One B-rep face of a CAD part: STEP entity #880.
In plain terms, the planar face has unit normal (1, 0, 0).
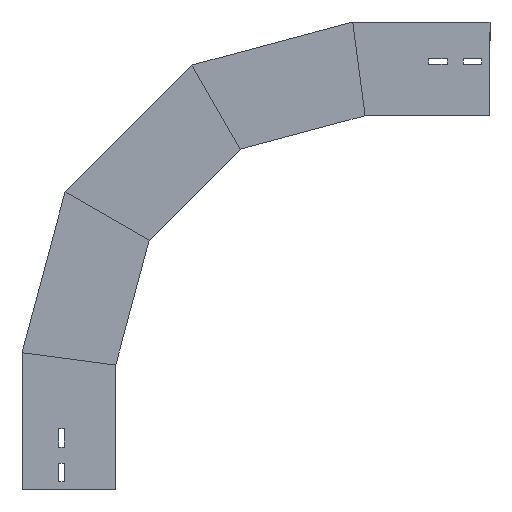
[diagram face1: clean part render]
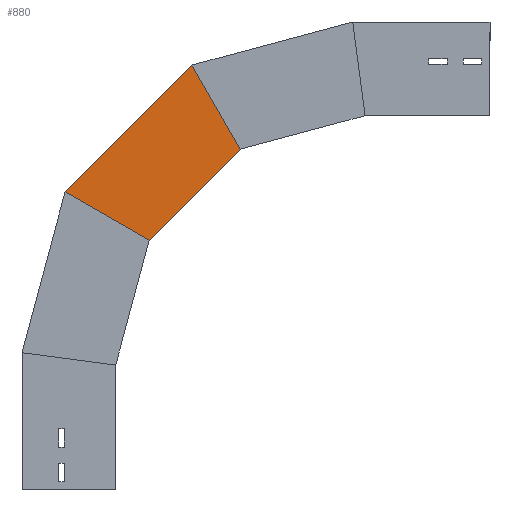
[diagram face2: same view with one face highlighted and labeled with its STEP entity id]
Its self-contained STEP definition (entity closure, numbers rounded to 3 decimals):
#38 = VECTOR ( 'NONE', #432, 1000. ) ;
#131 = LINE ( 'NONE', #1875, #38 ) ;
#132 = AXIS2_PLACEMENT_3D ( 'NONE', #1289, #1869, #224 ) ;
#134 = ORIENTED_EDGE ( 'NONE', *, *, #1280, .F. ) ;
#196 = EDGE_CURVE ( 'NONE', #447, #277, #1437, .T. ) ;
#224 = DIRECTION ( 'NONE',  ( 0., 0., -1. ) ) ;
#277 = VERTEX_POINT ( 'NONE', #496 ) ;
#383 = FACE_OUTER_BOUND ( 'NONE', #837, .T. ) ;
#409 = ORIENTED_EDGE ( 'NONE', *, *, #702, .T. ) ;
#413 = DIRECTION ( 'NONE',  ( 0., -0.707, 0.707 ) ) ;
#429 = CARTESIAN_POINT ( 'NONE',  ( 0., -40.117, 299.719 ) ) ;
#432 = DIRECTION ( 'NONE',  ( 0., -0.5, -0.866 ) ) ;
#447 = VERTEX_POINT ( 'NONE', #429 ) ;
#496 = CARTESIAN_POINT ( 'NONE',  ( 0., -149.719, 409.32 ) ) ;
#534 = DIRECTION ( 'NONE',  ( 0., -0.866, -0.5 ) ) ;
#545 = LINE ( 'NONE', #1715, #1818 ) ;
#583 = VERTEX_POINT ( 'NONE', #1326 ) ;
#628 = CARTESIAN_POINT ( 'NONE',  ( 0., -91.484, 510.185 ) ) ;
#702 = EDGE_CURVE ( 'NONE', #583, #1456, #1086, .T. ) ;
#734 = CARTESIAN_POINT ( 'NONE',  ( 0., -16.599, 276.201 ) ) ;
#788 = DIRECTION ( 'NONE',  ( 0., -0.707, 0.707 ) ) ;
#808 = VECTOR ( 'NONE', #413, 1000. ) ;
#837 = EDGE_LOOP ( 'NONE', ( #409, #1589, #1087, #134 ) ) ;
#880 = ADVANCED_FACE ( 'NONE', ( #383 ), #1555, .T. ) ;
#1086 = LINE ( 'NONE', #1504, #1170 ) ;
#1087 = ORIENTED_EDGE ( 'NONE', *, *, #196, .F. ) ;
#1170 = VECTOR ( 'NONE', #788, 1000. ) ;
#1280 = EDGE_CURVE ( 'NONE', #583, #447, #545, .T. ) ;
#1289 = CARTESIAN_POINT ( 'NONE',  ( 0., -16.599, 276.201 ) ) ;
#1326 = CARTESIAN_POINT ( 'NONE',  ( 0., 60.748, 357.953 ) ) ;
#1437 = LINE ( 'NONE', #734, #808 ) ;
#1456 = VERTEX_POINT ( 'NONE', #628 ) ;
#1504 = CARTESIAN_POINT ( 'NONE',  ( 0., 62.95, 355.751 ) ) ;
#1555 = PLANE ( 'NONE',  #132 ) ;
#1589 = ORIENTED_EDGE ( 'NONE', *, *, #1765, .T. ) ;
#1715 = CARTESIAN_POINT ( 'NONE',  ( 0., -78.533, 277.539 ) ) ;
#1765 = EDGE_CURVE ( 'NONE', #1456, #277, #131, .T. ) ;
#1818 = VECTOR ( 'NONE', #534, 1000. ) ;
#1869 = DIRECTION ( 'NONE',  ( 1., 0., 0. ) ) ;
#1875 = CARTESIAN_POINT ( 'NONE',  ( 0., -174.081, 367.123 ) ) ;
